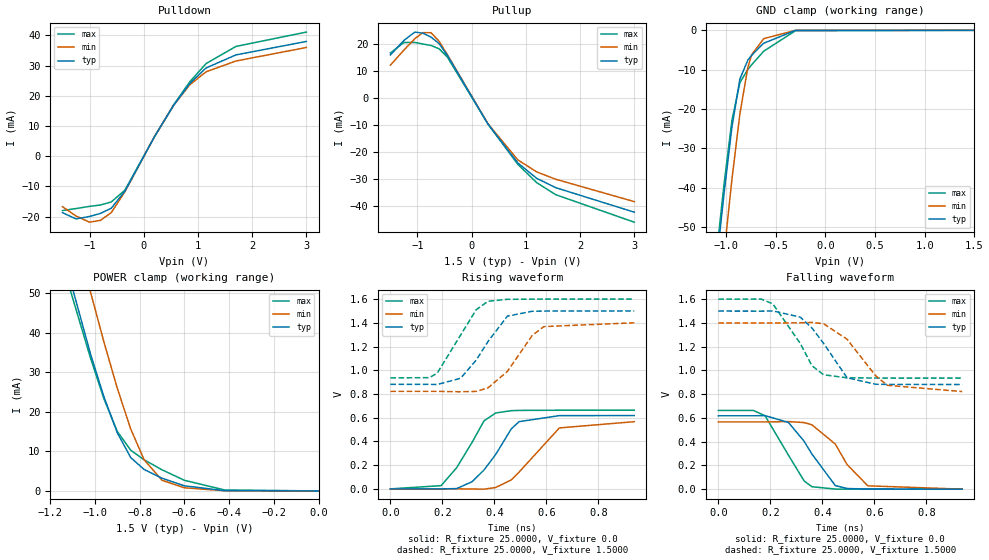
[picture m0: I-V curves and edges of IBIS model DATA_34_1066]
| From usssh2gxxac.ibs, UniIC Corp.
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|   Model DATA_34_1066
[Model]  DATA_34_1066
Model_type I/O
Polarity   Non-Inverting
Enable   Active-High
Vinl =   0.60000000V
Vinh =   0.90000000V
Vmeas =   0.750000000V
Rref =   25.00000000
Vref =   0.75000000V
C_comp   1.6160pF   1.5990pF   1.6430pF
[Temperature Range]   25.0000   95.0000   0.0
[Voltage Range]   1.5000V   1.4000V   1.6000V
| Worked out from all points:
|   slope of the pulldown table from 0 to 0.225 V, typ, clamps not added: 30.8 ohm
|   slope of the pullup table from 0 to 0.225 V, typ, clamps not added: 30.4 ohm
|   GND clamp passes 1 mA (typ) near -0.50 V on its own axis
|   POWER clamp passes 1 mA (typ) near -0.58 V on its own axis
|   rising waveform, R_fixture 25.0000, V_fixture 0.0: 20-80 % time 115ps typ, 130ps min, 108ps max; typ from 0 V to 0.618 V
|   rising waveform, R_fixture 25.0000, V_fixture 1.5000: 20-80 % time 113ps typ, 116ps min, 104ps max; typ from 0.881 V to 1.5 V
|   falling waveform, R_fixture 25.0000, V_fixture 0.0: 20-80 % time 110ps typ, 112ps min, 101ps max; typ from 0.618 V to 0 V
|   falling waveform, R_fixture 25.0000, V_fixture 1.5000: 20-80 % time 112ps typ, 127ps min, 105ps max; typ from 1.5 V to 0.881 V
[Pulldown]
|Voltage   I(typ)   I(min)   I(max)
-1.5V     -18.7mA    -16.7mA    -18mA
-1.25V    -20.76mA   -19.8mA    -17.33mA
-1V       -19.96mA   -21.85mA   -16.61mA
-800mV    -18.94mA   -21.24mA   -16.16mA
-600mV    -17.23mA   -18.69mA   -15.15mA
-350mV    -11.62mA   -11.84mA   -11.29mA
200mV     6.523mA    6.58mA     6.518mA
550mV     16.83mA    16.81mA    16.97mA
850mV     24.09mA    23.66mA    24.66mA
1.15V     29.22mA    27.95mA    30.67mA
1.7V      33.54mA    31.52mA    36.35mA
3V        38mA       36mA       41.1mA
[Pullup]
|Voltage   I(typ)   I(min)   I(max)
-1.5V     15.8mA     12mA       16.5mA
-1.25V    21.14mA    17.6mA     20.39mA
-1.05V    24.23mA    21.76mA    20.4mA
-900mV    23.84mA    24.02mA    19.83mA
-750mV    22.38mA    24mA       19.29mA
-600mV    19.94mA    20.83mA    18.05mA
-450mV    15.66mA    15.92mA    15.03mA
300mV     -9.744mA   -9.622mA   -9.709mA
850mV     -24.07mA   -22.95mA   -24.6mA
1.2V      -29.82mA   -27.44mA   -31.4mA
1.55V     -33.24mA   -30.13mA   -35.83mA
3V        -42.3mA    -38.4mA    -46mA
[GND_clamp]
|Voltage   I(typ)   I(min)   I(max)
-1.5V     -169mA     -189.1mA   -163.8mA
-1.14V    -70.71mA   -88.3mA    -68.32mA
-1.1V     -60.74mA   -77.66mA   -58.33mA
-1.06V    -51.03mA   -67.22mA   -48.61mA
-1.02V    -41.65mA   -57.06mA   -39.27mA
-940mV    -24.55mA   -37.9mA    -22.88mA
-860mV    -12.39mA   -21.26mA   -13.32mA
-780mV    -7.577mA   -9.433mA   -9.942mA
-740mV    -6.329mA   -6.125mA   -8.71mA
-620mV    -3.273mA   -2.113mA   -5.305mA
-300mV    -11.81uA   -4.878uA   -91.71uA
1.5V      4.577nA    23.6nA     33.33nA
[POWER_clamp]
|Voltage   I(typ)   I(min)   I(max)
-1.5V     143.7mA    161.7mA    138.1mA
-1.22V    77.56mA    95.29mA    73.32mA
-1.12V    55.19mA    72.34mA    52.54mA
-1.02V    34.59mA    50.23mA    33.56mA
-960mV    23.77mA    37.63mA    23.28mA
-900mV    14.66mA    25.9mA     15mA
-840mV    8.415mA    15.63mA    10.28mA
-780mV    5.408mA    7.848mA    7.861mA
-700mV    3.206mA    2.693mA    5.332mA
-600mV    1.29mA     794.5uA    2.681mA
-420mV    69.47uA    44.47uA    238.7uA
0V        4.577nA    6.249nA    39.08nA
[Ramp]
| variable   typ   min   max
dV/dt_r  0.3707/0.1151n   0.3398/0.1312n   0.3978/0.1081n
dV/dt_f  0.3712/0.1121n   0.3468/0.1264n   0.3986/0.1049n
R_load = 25.0000
[Rising Waveform]
R_fixture= 25.0000
V_fixture= 0.0
V_fixture_min= 0.0
V_fixture_max= 0.0
|time   V(typ)   V(min)   V(max)
0s        0V         0V         0V
195ps     -137.5uV   111.6uV    27.18mV
255ps     2.544mV    337.2uV    178.8mV
315ps     61.22mV    -1.07mV    395mV
360ps     158.9mV    -2.401mV   573.3mV
405ps     290.2mV    11.68mV    639.6mV
465ps     505.8mV    75.74mV    659.2mV
495ps     566.8mV    141.5mV    661.4mV
650ps     617.4mV    514mV      663mV
938ps     617.9mV    566.4mV    663mV
[Rising Waveform]
R_fixture= 25.0000
V_fixture= 1.5000
V_fixture_min= 1.4000
V_fixture_max= 1.6000
|time   V(typ)   V(min)   V(max)
0s        881.4mV    822mV      935.7mV
150ps     881mV      822.1mV    937.7mV
180ps     879.7mV    822.1mV    975.2mV
270ps     932.4mV    818.6mV    1.296V
330ps     1.085V     821.5mV    1.51V
375ps     1.241V     850.9mV    1.581V
450ps     1.456V     989.9mV    1.598V
545ps     1.497V     1.292V     1.599V
590ps     1.499V     1.368V     1.6V
938ps     1.5V       1.4V       1.6V
[Falling Waveform]
R_fixture= 25.0000
V_fixture= 0.0
V_fixture_min= 0.0
V_fixture_max= 0.0
|time   V(typ)   V(min)   V(max)
0s        617.9mV    566.4mV    663mV
135ps     617.9mV    566.3mV    662.9mV
180ps     619mV      566.3mV    618.1mV
270ps     561.8mV    569.1mV    285.5mV
330ps     403.3mV    560.9mV    69.54mV
360ps     295.8mV    542.3mV    20.56mV
450ps     30.34mV    380.2mV    681.6uV
495ps     5.644mV    208.2mV    119.6uV
575ps     376.6uV    28.24mV    6.884uV
938ps     0V         0V         0V
[Falling Waveform]
R_fixture= 25.0000
V_fixture= 1.5000
V_fixture_min= 1.4000
V_fixture_max= 1.6000
|time   V(typ)   V(min)   V(max)
0s        1.5V       1.4V       1.6V
165ps     1.499V     1.4V       1.601V
210ps     1.501V     1.399V     1.56V
315ps     1.449V     1.401V     1.228V
360ps     1.358V     1.404V     1.04V
405ps     1.228V     1.393V     963.5mV
495ps     938.3mV    1.263V     937.6mV
605ps     883.7mV    955.6mV    935.8mV
650ps     882.1mV    874.7mV    935.7mV
938ps     881.4mV    822.1mV    935.7mV
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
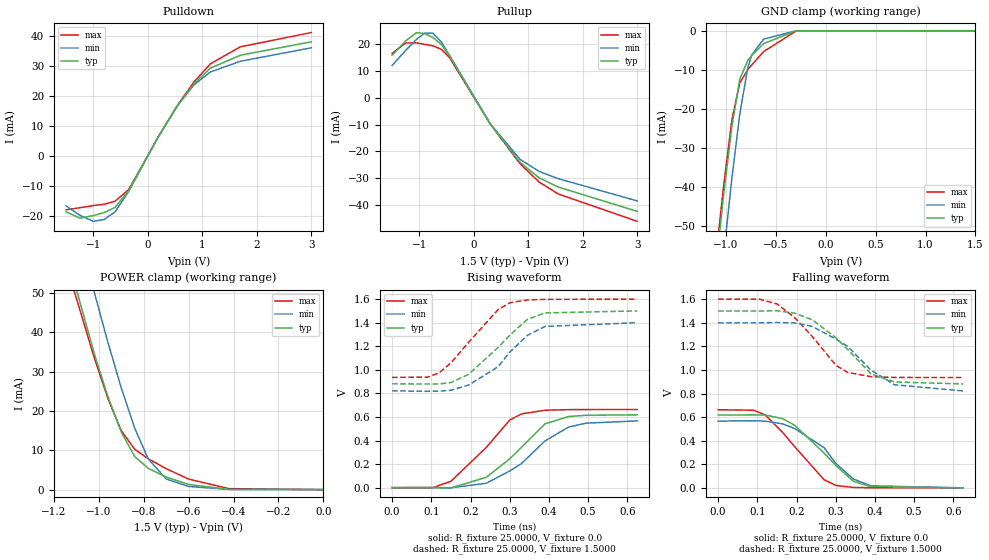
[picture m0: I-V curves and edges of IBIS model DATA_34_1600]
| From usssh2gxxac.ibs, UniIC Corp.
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|   Model DATA_34_1600
[Model]  DATA_34_1600
Model_type I/O
Polarity   Non-Inverting
Enable   Active-High
Vinl =   0.60000000V
Vinh =   0.90000000V
Vmeas =   0.750000000V
Rref =   25.00000000
Vref =   0.75000000V
C_comp   1.6160pF   1.5990pF   1.6430pF
[Temperature Range]   25.0000   95.0000   0.0
[Voltage Range]   1.5000V   1.4000V   1.6000V
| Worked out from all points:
|   slope of the pulldown table from 0 to 0.225 V, typ, clamps not added: 30.8 ohm
|   slope of the pullup table from 0 to 0.225 V, typ, clamps not added: 30.4 ohm
|   GND clamp passes 1 mA (typ) near -0.50 V on its own axis
|   POWER clamp passes 1 mA (typ) near -0.58 V on its own axis
|   rising waveform, R_fixture 25.0000, V_fixture 0.0: 20-80 % time 115ps typ, 125ps min, 108ps max; typ from 0 V to 0.618 V
|   rising waveform, R_fixture 25.0000, V_fixture 1.5000: 20-80 % time 113ps typ, 111ps min, 104ps max; typ from 0.881 V to 1.5 V
|   falling waveform, R_fixture 25.0000, V_fixture 0.0: 20-80 % time 110ps typ, 107ps min, 101ps max; typ from 0.618 V to 0 V
|   falling waveform, R_fixture 25.0000, V_fixture 1.5000: 20-80 % time 112ps typ, 122ps min, 105ps max; typ from 1.5 V to 0.882 V
[Pulldown]
|Voltage   I(typ)   I(min)   I(max)
-1.5V     -18.7mA    -16.7mA    -18mA
-1.25V    -20.76mA   -19.8mA    -17.33mA
-1V       -19.96mA   -21.85mA   -16.61mA
-800mV    -18.94mA   -21.24mA   -16.16mA
-600mV    -17.23mA   -18.69mA   -15.15mA
-350mV    -11.62mA   -11.84mA   -11.29mA
200mV     6.523mA    6.58mA     6.518mA
550mV     16.83mA    16.81mA    16.97mA
850mV     24.09mA    23.66mA    24.66mA
1.15V     29.22mA    27.95mA    30.67mA
1.7V      33.54mA    31.52mA    36.35mA
3V        38mA       36mA       41.1mA
[Pullup]
|Voltage   I(typ)   I(min)   I(max)
-1.5V     15.8mA     12mA       16.5mA
-1.25V    21.14mA    17.6mA     20.39mA
-1.05V    24.23mA    21.76mA    20.4mA
-900mV    23.84mA    24.02mA    19.83mA
-750mV    22.38mA    24mA       19.29mA
-600mV    19.94mA    20.83mA    18.05mA
-450mV    15.66mA    15.92mA    15.03mA
300mV     -9.744mA   -9.622mA   -9.709mA
850mV     -24.07mA   -22.95mA   -24.6mA
1.2V      -29.82mA   -27.44mA   -31.4mA
1.55V     -33.24mA   -30.13mA   -35.83mA
3V        -42.3mA    -38.4mA    -46mA
[GND_clamp]
|Voltage   I(typ)   I(min)   I(max)
-1.5V     -169mA     -189.1mA   -163.8mA
-1.14V    -70.71mA   -88.3mA    -68.32mA
-1.1V     -60.74mA   -77.66mA   -58.33mA
-1.06V    -51.03mA   -67.22mA   -48.61mA
-1.02V    -41.65mA   -57.06mA   -39.27mA
-940mV    -24.55mA   -37.9mA    -22.88mA
-860mV    -12.39mA   -21.26mA   -13.32mA
-780mV    -7.577mA   -9.433mA   -9.942mA
-740mV    -6.329mA   -6.125mA   -8.71mA
-620mV    -3.273mA   -2.113mA   -5.305mA
-300mV    -11.81uA   -4.878uA   -91.71uA
1.5V      4.577nA    23.6nA     33.33nA
[POWER_clamp]
|Voltage   I(typ)   I(min)   I(max)
-1.5V     143.7mA    161.7mA    138.1mA
-1.22V    77.56mA    95.29mA    73.32mA
-1.12V    55.19mA    72.34mA    52.54mA
-1.02V    34.59mA    50.23mA    33.56mA
-960mV    23.77mA    37.63mA    23.28mA
-900mV    14.66mA    25.9mA     15mA
-840mV    8.415mA    15.63mA    10.28mA
-780mV    5.408mA    7.848mA    7.861mA
-700mV    3.206mA    2.693mA    5.332mA
-600mV    1.29mA     794.5uA    2.681mA
-420mV    69.47uA    44.47uA    238.7uA
0V        4.577nA    6.249nA    39.08nA
[Ramp]
| variable   typ   min   max
dV/dt_r  0.3707/0.1151n   0.3398/0.1312n   0.3978/0.1081n
dV/dt_f  0.3712/0.1121n   0.3468/0.1264n   0.3986/0.1049n
R_load = 25.0000
[Rising Waveform]
R_fixture= 25.0000
V_fixture= 0.0
V_fixture_min= 0.0
V_fixture_max= 0.0
|time   V(typ)   V(min)   V(max)
0s        0V         0V         0V
105ps     170.3uV    313.4uV    979.3uV
150ps     -1.852mV   -1.07mV    54.16mV
240ps     87.14mV    37.02mV    340.8mV
300ps     244.2mV    141.5mV    573.3mV
330ps     343.1mV    204.5mV    625.9mV
390ps     541.5mV    396.8mV    657mV
450ps     603.3mV    514mV      662mV
495ps     614.4mV    547.4mV    662.7mV
625ps     617.9mV    566.4mV    663mV
[Rising Waveform]
R_fixture= 25.0000
V_fixture= 1.5000
V_fixture_min= 1.4000
V_fixture_max= 1.6000
|time   V(typ)   V(min)   V(max)
0s        881.4mV    822mV      935.7mV
90.91ps   879.7mV    817.7mV    937.7mV
120ps     880.1mV    818.6mV    975.2mV
150ps     891.6mV    826.5mV    1.059V
195ps     961.6mV    870.7mV    1.233V
270ps     1.189V     1.025V     1.51V
300ps     1.293V     1.15V      1.569V
345ps     1.428V     1.292V     1.593V
390ps     1.483V     1.368V     1.598V
625ps     1.5V       1.4V       1.6V
[Falling Waveform]
R_fixture= 25.0000
V_fixture= 0.0
V_fixture_min= 0.0
V_fixture_max= 0.0
|time   V(typ)   V(min)   V(max)
0s        617.9mV    566.4mV    662.9mV
90.91ps   619mV      569.1mV    658.6mV
120ps     617.7mV    566mV      618.1mV
165ps     586.9mV    542.3mV    468.6mV
195ps     531.4mV    503.8mV    350.2mV
270ps     295.8mV    341.6mV    69.54mV
300ps     190.9mV    208.2mV    20.56mV
345ps     55.27mV    74.32mV    3.695mV
390ps     9.881mV    17.46mV    681.6uV
625ps     0V         0V         0V
[Falling Waveform]
R_fixture= 25.0000
V_fixture= 1.5000
V_fixture_min= 1.4000
V_fixture_max= 1.6000
|time   V(typ)   V(min)   V(max)
0s        1.5V       1.4V       1.6V
105ps     1.5V       1.4V       1.601V
150ps     1.503V     1.403V     1.56V
195ps     1.482V     1.399V     1.445V
240ps     1.426V     1.37V      1.285V
300ps     1.274V     1.263V     1.04V
330ps     1.176V     1.201V     979.3mV
390ps     965.9mV    998.2mV    943.1mV
450ps     898.3mV    874.7mV    936.9mV
625ps     881.5mV    822.1mV    935.7mV
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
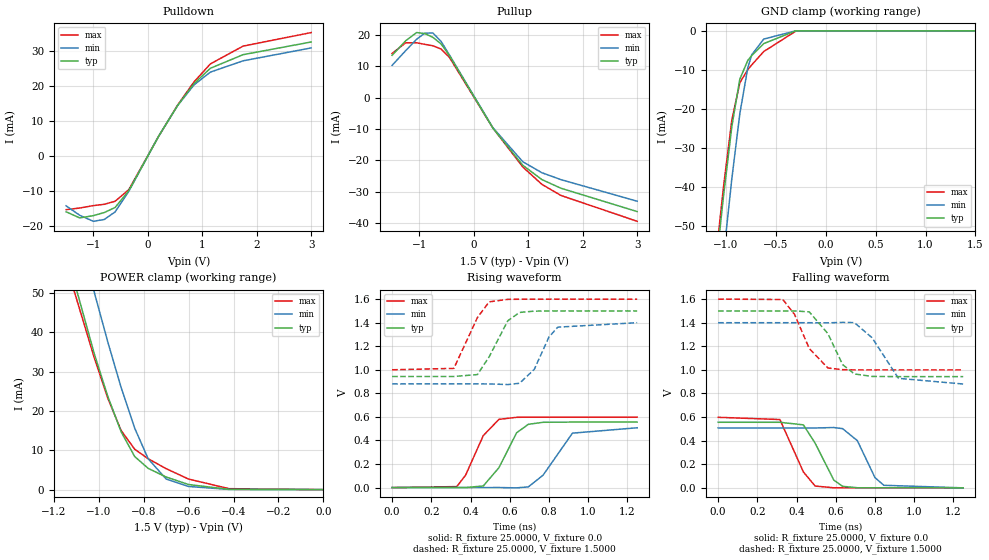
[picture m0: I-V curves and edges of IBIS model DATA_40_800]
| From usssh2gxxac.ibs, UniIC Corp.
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|   Model DATA_40_800
[Model]  DATA_40_800
Model_type I/O
Polarity   Non-Inverting
Enable   Active-High
Vinl =   0.60000000V
Vinh =   0.90000000V
Vmeas =   0.750000000V
Rref =   25.00000000
Vref =   0.75000000V
C_comp   1.6160pF   1.5990pF   1.6430pF
[Temperature Range]   25.0000   95.0000   0.0
[Voltage Range]   1.5000V   1.4000V   1.6000V
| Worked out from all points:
|   slope of the pulldown table from 0 to 0.225 V, typ, clamps not added: 35.8 ohm
|   slope of the pullup table from 0 to 0.225 V, typ, clamps not added: 35.3 ohm
|   GND clamp passes 1 mA (typ) near -0.50 V on its own axis
|   POWER clamp passes 1 mA (typ) near -0.58 V on its own axis
|   rising waveform, R_fixture 25.0000, V_fixture 0.0: 20-80 % time 104ps typ, 113ps min, 96.5ps max; typ from 0 V to 0.556 V
|   rising waveform, R_fixture 25.0000, V_fixture 1.5000: 20-80 % time 102ps typ, 90.8ps min, 93.7ps max; typ from 0.943 V to 1.5 V
|   falling waveform, R_fixture 25.0000, V_fixture 0.0: 20-80 % time 99.1ps typ, 87.6ps min, 91.1ps max; typ from 0.556 V to 0 V
|   falling waveform, R_fixture 25.0000, V_fixture 1.5000: 20-80 % time 102ps typ, 109ps min, 95.2ps max; typ from 1.5 V to 0.943 V
[Pulldown]
|Voltage   I(typ)   I(min)   I(max)
-1.5V     -16mA      -14.3mA    -15.4mA
-1.25V    -17.76mA   -17mA      -14.93mA
-1V       -17.11mA   -18.73mA   -14.24mA
-800mV    -16.23mA   -18.22mA   -13.86mA
-600mV    -14.78mA   -16.05mA   -13mA
-350mV    -9.992mA   -10.19mA   -9.704mA
200mV     5.609mA    5.658mA    5.604mA
550mV     14.47mA    14.45mA    14.59mA
850mV     20.7mA     20.32mA    21.19mA
1.15V     25.08mA    23.98mA    26.33mA
1.75V     28.97mA    27.21mA    31.42mA
3V        32.6mA     30.9mA     35.3mA
[Pullup]
|Voltage   I(typ)   I(min)   I(max)
-1.5V     13.5mA     10.3mA     14.1mA
-1.25V    18.14mA    15mA       17.49mA
-1.05V    20.75mA    18.62mA    17.5mA
-900mV    20.45mA    20.57mA    17mA
-750mV    19.21mA    20.61mA    16.54mA
-600mV    17.13mA    17.9mA     15.49mA
-450mV    13.47mA    13.7mA     12.92mA
350mV     -9.677mA   -9.536mA   -9.657mA
900mV     -21.53mA   -20.42mA   -22.09mA
1.25V     -26.1mA    -23.92mA   -27.61mA
1.6V      -28.86mA   -26.12mA   -31.16mA
3V        -36.3mA    -33mA      -39.4mA
[GND_clamp]
|Voltage   I(typ)   I(min)   I(max)
-1.5V     -169mA     -189.1mA   -163.8mA
-1.14V    -70.71mA   -88.3mA    -68.32mA
-1.1V     -60.74mA   -77.66mA   -58.33mA
-1.06V    -51.03mA   -67.22mA   -48.61mA
-1.02V    -41.65mA   -57.06mA   -39.27mA
-940mV    -24.55mA   -37.9mA    -22.88mA
-860mV    -12.39mA   -21.26mA   -13.32mA
-780mV    -7.577mA   -9.433mA   -9.942mA
-740mV    -6.329mA   -6.125mA   -8.71mA
-620mV    -3.273mA   -2.113mA   -5.305mA
-300mV    -11.81uA   -4.878uA   -91.71uA
1.5V      4.577nA    23.6nA     33.33nA
[POWER_clamp]
|Voltage   I(typ)   I(min)   I(max)
-1.5V     143.7mA    161.7mA    138.1mA
-1.22V    77.56mA    95.29mA    73.32mA
-1.12V    55.19mA    72.34mA    52.54mA
-1.02V    34.59mA    50.23mA    33.56mA
-960mV    23.77mA    37.63mA    23.28mA
-900mV    14.66mA    25.9mA     15mA
-840mV    8.415mA    15.63mA    10.28mA
-780mV    5.408mA    7.848mA    7.861mA
-700mV    3.206mA    2.693mA    5.332mA
-600mV    1.29mA     794.5uA    2.681mA
-420mV    69.47uA    44.47uA    238.7uA
0V        4.577nA    6.249nA    39.08nA
[Ramp]
| variable   typ   min   max
dV/dt_r  0.3336/0.1041n   0.3046/0.1129n   0.3589/96.4996p
dV/dt_f  0.3342/0.1019n   0.3119/0.1089n   0.3600/95.1948p
R_load = 25.0000
[Rising Waveform]
R_fixture= 25.0000
V_fixture= 0.0
V_fixture_min= 0.0
V_fixture_max= 0.0
|time   V(typ)   V(min)   V(max)
0s        0V         0V         0V
330ps     157.1uV    769.7nV    8.258mV
375ps     245.2uV    -5.347uV   105.6mV
465ps     13.51mV    37.31uV    441.1mV
545ps     168.9mV    313.8uV    579.1mV
635ps     465.2mV    -2.504mV   596.6mV
695ps     537.1mV    5.744mV    597.8mV
770ps     554.3mV    105.1mV    598mV
920ps     556mV      462.1mV    598.1mV
1.25ns    556mV      507.7mV    598.1mV
[Rising Waveform]
R_fixture= 25.0000
V_fixture= 1.5000
V_fixture_min= 1.4000
V_fixture_max= 1.6000
|time   V(typ)   V(min)   V(max)
0s        943mV      880.2mV    1V
315ps     943.1mV    880.2mV    1.012V
435ps     959.4mV    880.4mV    1.443V
495ps     1.11V      880mV      1.577V
590ps     1.416V     874.6mV    1.598V
650ps     1.487V     885.9mV    1.599V
725ps     1.498V     1.003V     1.6V
800ps     1.499V     1.278V     1.6V
845ps     1.5V       1.362V     1.6V
1.25ns    1.5V       1.4V       1.6V
[Falling Waveform]
R_fixture= 25.0000
V_fixture= 0.0
V_fixture_min= 0.0
V_fixture_max= 0.0
|time   V(typ)   V(min)   V(max)
0s        556mV      507.7mV    598.1mV
315ps     555.9mV    507.7mV    579.3mV
435ps     534.1mV    507.6mV    134.8mV
495ps     378.3mV    507.7mV    15.11mV
590ps     66mV       511.5mV    582.4uV
635ps     12.97mV    501.9mV    113.9uV
710ps     954.7uV    400.5mV    7.593uV
800ps     27.03uV    87.05mV    0V
845ps     5.312uV    21.79mV    0V
1.25ns    0V         837.3nV    0V
[Falling Waveform]
R_fixture= 25.0000
V_fixture= 1.5000
V_fixture_min= 1.4000
V_fixture_max= 1.6000
|time   V(typ)   V(min)   V(max)
0s        1.5V       1.4V       1.6V
330ps     1.499V     1.4V       1.597V
390ps     1.5V       1.4V       1.47V
465ps     1.492V     1.4V       1.181V
560ps     1.307V     1.399V     1.016V
635ps     1.045V     1.403V     1.002V
695ps     965.7mV    1.401V     1V
785ps     944.6mV    1.273V     1V
920ps     943.1mV    928.4mV    1V
1.25ns    943mV      880.3mV    1V
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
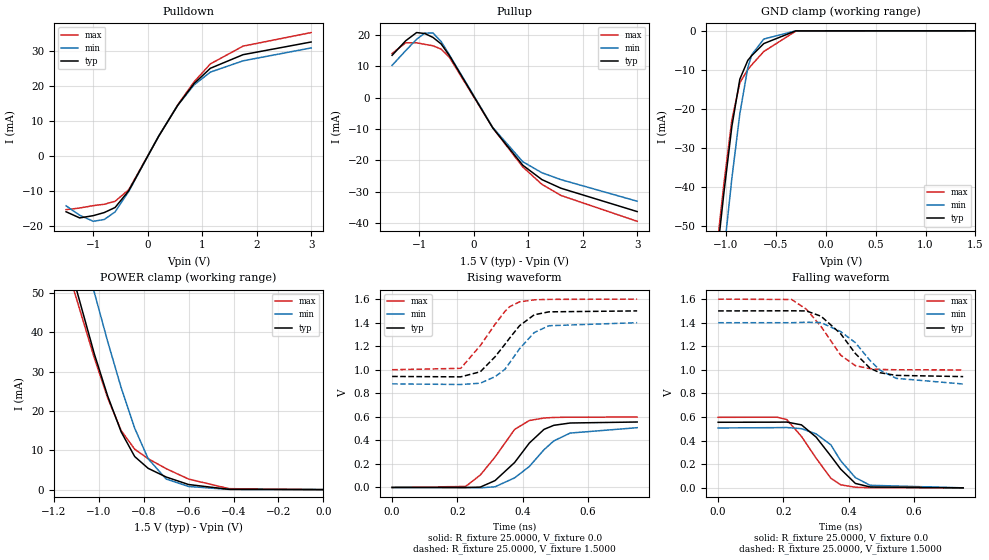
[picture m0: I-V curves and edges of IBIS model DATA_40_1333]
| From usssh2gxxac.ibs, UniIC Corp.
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|   Model DATA_40_1333
[Model]  DATA_40_1333
Model_type I/O
Polarity   Non-Inverting
Enable   Active-High
Vinl =   0.60000000V
Vinh =   0.90000000V
Vmeas =   0.750000000V
Rref =   25.00000000
Vref =   0.75000000V
C_comp   1.6160pF   1.5990pF   1.6430pF
[Temperature Range]   25.0000   95.0000   0.0
[Voltage Range]   1.5000V   1.4000V   1.6000V
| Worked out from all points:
|   slope of the pulldown table from 0 to 0.225 V, typ, clamps not added: 35.8 ohm
|   slope of the pullup table from 0 to 0.225 V, typ, clamps not added: 35.3 ohm
|   GND clamp passes 1 mA (typ) near -0.50 V on its own axis
|   POWER clamp passes 1 mA (typ) near -0.58 V on its own axis
|   rising waveform, R_fixture 25.0000, V_fixture 0.0: 20-80 % time 104ps typ, 115ps min, 96.5ps max; typ from 0 V to 0.556 V
|   rising waveform, R_fixture 25.0000, V_fixture 1.5000: 20-80 % time 96.8ps typ, 90.8ps min, 93.7ps max; typ from 0.943 V to 1.5 V
|   falling waveform, R_fixture 25.0000, V_fixture 0.0: 20-80 % time 94.1ps typ, 87.6ps min, 91.1ps max; typ from 0.556 V to 0 V
|   falling waveform, R_fixture 25.0000, V_fixture 1.5000: 20-80 % time 102ps typ, 111ps min, 95.2ps max; typ from 1.5 V to 0.943 V
[Pulldown]
|Voltage   I(typ)   I(min)   I(max)
-1.5V     -16mA      -14.3mA    -15.4mA
-1.25V    -17.76mA   -17mA      -14.93mA
-1V       -17.11mA   -18.73mA   -14.24mA
-800mV    -16.23mA   -18.22mA   -13.86mA
-600mV    -14.78mA   -16.05mA   -13mA
-350mV    -9.992mA   -10.19mA   -9.704mA
200mV     5.609mA    5.658mA    5.604mA
550mV     14.47mA    14.45mA    14.59mA
850mV     20.7mA     20.32mA    21.19mA
1.15V     25.08mA    23.98mA    26.33mA
1.75V     28.97mA    27.21mA    31.42mA
3V        32.6mA     30.9mA     35.3mA
[Pullup]
|Voltage   I(typ)   I(min)   I(max)
-1.5V     13.5mA     10.3mA     14.1mA
-1.25V    18.14mA    15mA       17.49mA
-1.05V    20.75mA    18.62mA    17.5mA
-900mV    20.45mA    20.57mA    17mA
-750mV    19.21mA    20.61mA    16.54mA
-600mV    17.13mA    17.9mA     15.49mA
-450mV    13.47mA    13.7mA     12.92mA
350mV     -9.677mA   -9.536mA   -9.657mA
900mV     -21.53mA   -20.42mA   -22.09mA
1.25V     -26.1mA    -23.92mA   -27.61mA
1.6V      -28.86mA   -26.12mA   -31.16mA
3V        -36.3mA    -33mA      -39.4mA
[GND_clamp]
|Voltage   I(typ)   I(min)   I(max)
-1.5V     -169mA     -189.1mA   -163.8mA
-1.14V    -70.71mA   -88.3mA    -68.32mA
-1.1V     -60.74mA   -77.66mA   -58.33mA
-1.06V    -51.03mA   -67.22mA   -48.61mA
-1.02V    -41.65mA   -57.06mA   -39.27mA
-940mV    -24.55mA   -37.9mA    -22.88mA
-860mV    -12.39mA   -21.26mA   -13.32mA
-780mV    -7.577mA   -9.433mA   -9.942mA
-740mV    -6.329mA   -6.125mA   -8.71mA
-620mV    -3.273mA   -2.113mA   -5.305mA
-300mV    -11.81uA   -4.878uA   -91.71uA
1.5V      4.577nA    23.6nA     33.33nA
[POWER_clamp]
|Voltage   I(typ)   I(min)   I(max)
-1.5V     143.7mA    161.7mA    138.1mA
-1.22V    77.56mA    95.29mA    73.32mA
-1.12V    55.19mA    72.34mA    52.54mA
-1.02V    34.59mA    50.23mA    33.56mA
-960mV    23.77mA    37.63mA    23.28mA
-900mV    14.66mA    25.9mA     15mA
-840mV    8.415mA    15.63mA    10.28mA
-780mV    5.408mA    7.848mA    7.861mA
-700mV    3.206mA    2.693mA    5.332mA
-600mV    1.29mA     794.5uA    2.681mA
-420mV    69.47uA    44.47uA    238.7uA
0V        4.577nA    6.249nA    39.08nA
[Ramp]
| variable   typ   min   max
dV/dt_r  0.3336/0.1041n   0.3046/0.1129n   0.3589/96.4996p
dV/dt_f  0.3342/0.1019n   0.3119/0.1089n   0.3600/95.1948p
R_load = 25.0000
[Rising Waveform]
R_fixture= 25.0000
V_fixture= 0.0
V_fixture_min= 0.0
V_fixture_max= 0.0
|time   V(typ)   V(min)   V(max)
0s        0V         0V         0V
225ps     -1.177mV   -445.7uV   8.258mV
270ps     3.196mV    -3.475mV   105.6mV
315ps     58.01mV    5.744mV    258.1mV
375ps     212.1mV    81.61mV    493.1mV
420ps     377.3mV    178mV      568.7mV
465ps     493.7mV    321mV      590mV
495ps     527.9mV    395.6mV    594.7mV
545ps     547.6mV    462.1mV    597.1mV
750ps     556mV      507.7mV    598.1mV
[Rising Waveform]
R_fixture= 25.0000
V_fixture= 1.5000
V_fixture_min= 1.4000
V_fixture_max= 1.6000
|time   V(typ)   V(min)   V(max)
0s        943mV      880.2mV    1V
210ps     939.6mV    874.6mV    1.012V
270ps     982.9mV    885.9mV    1.205V
315ps     1.11V      941mV      1.386V
345ps     1.215V     1.003V     1.495V
360ps     1.27V      1.06V      1.536V
390ps     1.374V     1.178V     1.577V
435ps     1.467V     1.316V     1.594V
480ps     1.492V     1.374V     1.598V
750ps     1.5V       1.4V       1.6V
[Falling Waveform]
R_fixture= 25.0000
V_fixture= 0.0
V_fixture_min= 0.0
V_fixture_max= 0.0
|time   V(typ)   V(min)   V(max)
0s        556mV      507.7mV    598.1mV
180ps     557mV      510.5mV    599.1mV
210ps     557.8mV    511.5mV    579.3mV
255ps     534.1mV    501.9mV    436.1mV
300ps     430mV      457.4mV    251mV
345ps     269.6mV    364.7mV    81.51mV
375ps     159.1mV    230.3mV    26.07mV
420ps     37.64mV    87.05mV    5.109mV
465ps     7.592mV    21.79mV    1.015mV
750ps     0V         0V         0V
[Falling Waveform]
R_fixture= 25.0000
V_fixture= 1.5000
V_fixture_min= 1.4000
V_fixture_max= 1.6000
|time   V(typ)   V(min)   V(max)
0s        1.5V       1.4V       1.6V
225ps     1.501V     1.4V       1.597V
270ps     1.5V       1.404V     1.514V
315ps     1.455V     1.401V     1.368V
375ps     1.307V     1.325V     1.125V
420ps     1.139V     1.231V     1.036V
465ps     1.014V     1.079V     1.01V
495ps     976.2mV    998.9mV    1.004V
545ps     953.6mV    928.4mV    1.001V
750ps     943.1mV    880.4mV    1V
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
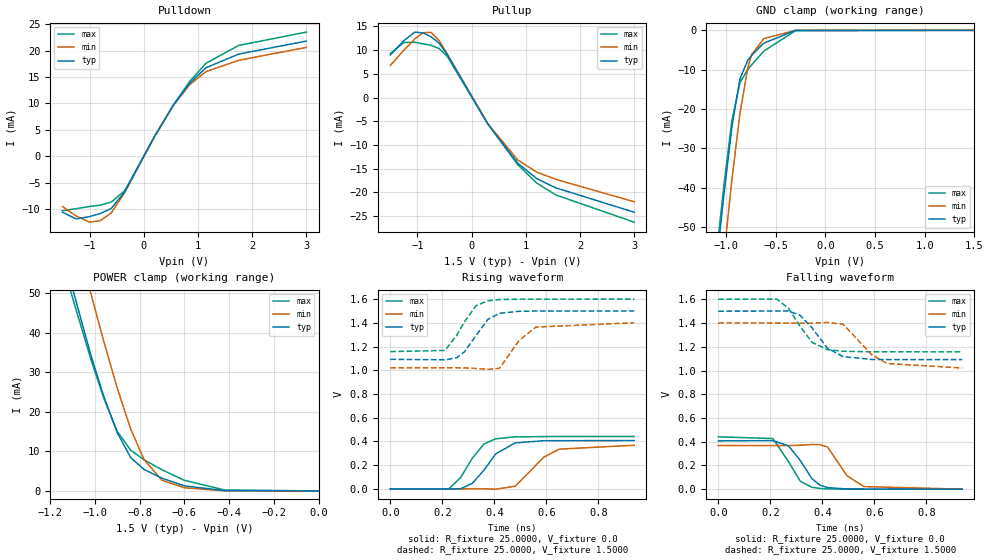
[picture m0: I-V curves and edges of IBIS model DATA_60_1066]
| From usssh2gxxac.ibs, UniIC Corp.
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|   Model DATA_60_1066
[Model]  DATA_60_1066
Model_type I/O
Polarity   Non-Inverting
Enable   Active-High
Vinl =   0.60000000V
Vinh =   0.90000000V
Vmeas =   0.750000000V
Rref =   25.00000000
Vref =   0.75000000V
C_comp   1.6160pF   1.5990pF   1.6430pF
[Temperature Range]   25.0000   95.0000   0.0
[Voltage Range]   1.5000V   1.4000V   1.6000V
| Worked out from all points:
|   slope of the pulldown table from 0 to 0.225 V, typ, clamps not added: 53.4 ohm
|   slope of the pullup table from 0 to 0.225 V, typ, clamps not added: 52.6 ohm
|   GND clamp passes 1 mA (typ) near -0.50 V on its own axis
|   POWER clamp passes 1 mA (typ) near -0.58 V on its own axis
|   rising waveform, R_fixture 25.0000, V_fixture 0.0: 20-80 % time 86.5ps typ, 100ps min, 79ps max; typ from 0 V to 0.407 V
|   rising waveform, R_fixture 25.0000, V_fixture 1.5000: 20-80 % time 78.8ps typ, 81.2ps min, 73.4ps max; typ from 1.09 V to 1.5 V
|   falling waveform, R_fixture 25.0000, V_fixture 0.0: 20-80 % time 75.8ps typ, 75.4ps min, 70.8ps max; typ from 0.407 V to 0 V
|   falling waveform, R_fixture 25.0000, V_fixture 1.5000: 20-80 % time 88.4ps typ, 97.1ps min, 81.8ps max; typ from 1.5 V to 1.09 V
[Pulldown]
|Voltage   I(typ)   I(min)   I(max)
-1.5V     -10.6mA    -9.5mA     -10.3mA
-1.25V    -11.86mA   -11.3mA    -9.93mA
-1V       -11.42mA   -12.48mA   -9.5mA
-800mV    -10.84mA   -12.17mA   -9.25mA
-600mV    -9.882mA   -10.74mA   -8.682mA
-350mV    -6.704mA   -6.838mA   -6.505mA
200mV     3.763mA    3.796mA    3.76mA
550mV     9.696mA    9.684mA    9.781mA
850mV     13.86mA    13.59mA    14.19mA
1.15V     16.76mA    16.02mA    17.61mA
1.75V     19.33mA    18.16mA    20.97mA
3V        21.8mA     20.6mA     23.5mA
[Pullup]
|Voltage   I(typ)   I(min)   I(max)
-1.5V     9mA        6.8mA      9.3mA
-1.25V    12.03mA    10mA       11.63mA
-1.05V    13.82mA    12.36mA    11.68mA
-900mV    13.65mA    13.69mA    11.34mA
-750mV    12.84mA    13.77mA    11.04mA
-600mV    11.47mA    12.01mA    10.35mA
-450mV    9.041mA    9.198mA    8.665mA
300mV     -5.62mA    -5.548mA   -5.6mA
850mV     -13.84mA   -13.18mA   -14.16mA
1.2V      -17.1mA    -15.73mA   -18.03mA
1.55V     -19.04mA   -17.25mA   -20.54mA
3V        -24.2mA    -22mA      -26.3mA
[GND_clamp]
|Voltage   I(typ)   I(min)   I(max)
-1.5V     -169mA     -189.1mA   -163.8mA
-1.14V    -70.71mA   -88.3mA    -68.32mA
-1.1V     -60.74mA   -77.66mA   -58.33mA
-1.06V    -51.03mA   -67.22mA   -48.61mA
-1.02V    -41.65mA   -57.06mA   -39.27mA
-940mV    -24.55mA   -37.9mA    -22.88mA
-860mV    -12.39mA   -21.26mA   -13.32mA
-780mV    -7.577mA   -9.433mA   -9.942mA
-740mV    -6.329mA   -6.125mA   -8.71mA
-620mV    -3.273mA   -2.113mA   -5.305mA
-300mV    -11.81uA   -4.878uA   -91.71uA
1.5V      4.577nA    23.6nA     33.33nA
[POWER_clamp]
|Voltage   I(typ)   I(min)   I(max)
-1.5V     143.7mA    161.7mA    138.1mA
-1.22V    77.56mA    95.29mA    73.32mA
-1.12V    55.19mA    72.34mA    52.54mA
-1.02V    34.59mA    50.23mA    33.56mA
-960mV    23.77mA    37.63mA    23.28mA
-900mV    14.66mA    25.9mA     15mA
-840mV    8.415mA    15.63mA    10.28mA
-780mV    5.408mA    7.848mA    7.861mA
-700mV    3.206mA    2.693mA    5.332mA
-600mV    1.29mA     794.5uA    2.681mA
-420mV    69.47uA    44.47uA    238.7uA
0V        4.577nA    6.249nA    39.08nA
[Ramp]
| variable   typ   min   max
dV/dt_r  0.2442/86.5366p   0.2207/98.3857p   0.2647/78.9981p
dV/dt_f  0.2448/88.3671p   0.2280/97.6364p   0.2658/81.8205p
R_load = 25.0000
[Rising Waveform]
R_fixture= 25.0000
V_fixture= 0.0
V_fixture_min= 0.0
V_fixture_max= 0.0
|time   V(typ)   V(min)   V(max)
0s        0V         0V         0V
225ps     -805.3uV   -18.23uV   1.139mV
270ps     1.751mV    133.5uV    95.42mV
315ps     46.46mV    528.8uV    258.4mV
360ps     157.9mV    548.9uV    378.8mV
405ps     295.1mV    -2.368mV   422mV
480ps     387.4mV    22.31mV    438.4mV
590ps     406mV      267mV      441mV
650ps     406.8mV    335.2mV    441.2mV
938ps     407mV      367.8mV    441.2mV
[Rising Waveform]
R_fixture= 25.0000
V_fixture= 1.5000
V_fixture_min= 1.4000
V_fixture_max= 1.6000
|time   V(typ)   V(min)   V(max)
0s        1.092V     1.02V      1.157V
210ps     1.088V     1.021V     1.167V
255ps     1.105V     1.021V     1.294V
285ps     1.156V     1.02V      1.409V
330ps     1.294V     1.015V     1.545V
375ps     1.429V     1.007V     1.585V
420ps     1.48V      1.017V     1.596V
495ps     1.497V     1.251V     1.599V
560ps     1.499V     1.364V     1.599V
938ps     1.5V       1.4V       1.6V
[Falling Waveform]
R_fixture= 25.0000
V_fixture= 0.0
V_fixture_min= 0.0
V_fixture_max= 0.0
|time   V(typ)   V(min)   V(max)
0s        407mV      367.9mV    441.2mV
210ps     408.9mV    367.7mV    426.7mV
270ps     365mV      367.4mV    232.5mV
315ps     242.9mV    370.3mV    67.61mV
360ps     89.18mV    376.5mV    16.03mV
390ps     34.49mV    375.2mV    6.06mV
420ps     13.4mV     355.8mV    2.344mV
495ps     1.268mV    112.9mV    209.2uV
560ps     131.4uV    21.72mV    32.08uV
938ps     0V         0V         0V
[Falling Waveform]
R_fixture= 25.0000
V_fixture= 1.5000
V_fixture_min= 1.4000
V_fixture_max= 1.6000
|time   V(typ)   V(min)   V(max)
0s        1.5V       1.4V       1.6V
225ps     1.501V     1.4V       1.602V
270ps     1.501V     1.399V     1.524V
315ps     1.464V     1.399V     1.371V
360ps     1.361V     1.399V     1.238V
420ps     1.187V     1.405V     1.176V
480ps     1.117V     1.39V      1.162V
590ps     1.093V     1.133V     1.158V
650ps     1.092V     1.059V     1.158V
938ps     1.092V     1.021V     1.157V
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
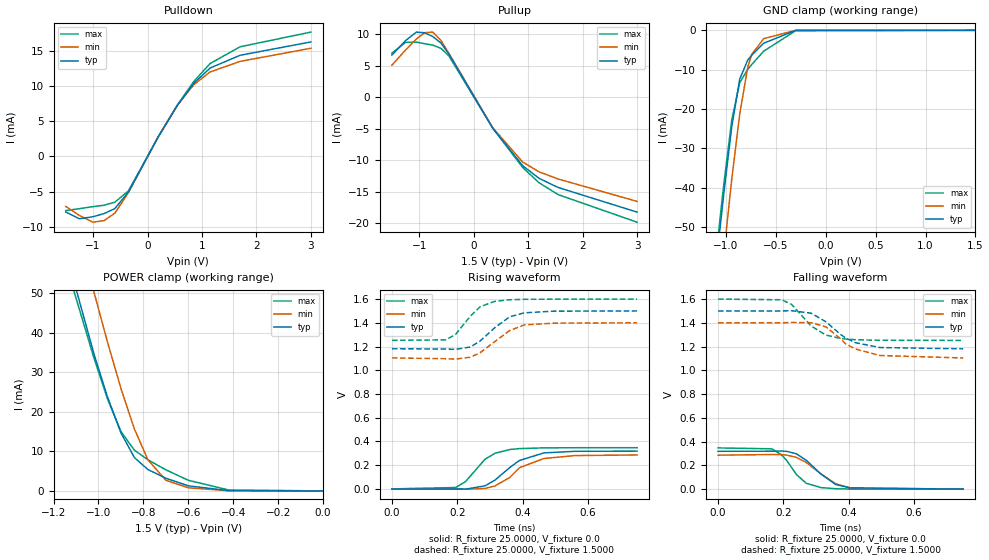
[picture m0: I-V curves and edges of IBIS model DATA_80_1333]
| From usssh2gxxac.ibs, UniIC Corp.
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|   Model DATA_80_1333
[Model]  DATA_80_1333
Model_type I/O
Polarity   Non-Inverting
Enable   Active-High
Vinl =   0.60000000V
Vinh =   0.90000000V
Vmeas =   0.750000000V
Rref =   25.00000000
Vref =   0.75000000V
C_comp   1.6160pF   1.5990pF   1.6430pF
[Temperature Range]   25.0000   95.0000   0.0
[Voltage Range]   1.5000V   1.4000V   1.6000V
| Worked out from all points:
|   slope of the pulldown table from 0 to 0.225 V, typ, clamps not added: 70.9 ohm
|   slope of the pullup table from 0 to 0.225 V, typ, clamps not added: 70 ohm
|   GND clamp passes 1 mA (typ) near -0.50 V on its own axis
|   POWER clamp passes 1 mA (typ) near -0.58 V on its own axis
|   rising waveform, R_fixture 25.0000, V_fixture 0.0: 20-80 % time 91.5ps typ, 90.7ps min, 71.4ps max; typ from 0 V to 0.319 V
|   rising waveform, R_fixture 25.0000, V_fixture 1.5000: 20-80 % time 82.5ps typ, 85.9ps min, 65.7ps max; typ from 1.18 V to 1.5 V
|   falling waveform, R_fixture 25.0000, V_fixture 0.0: 20-80 % time 79.2ps typ, 84.7ps min, 61.1ps max; typ from 0.319 V to 0 V
|   falling waveform, R_fixture 25.0000, V_fixture 1.5000: 20-80 % time 93.8ps typ, 90.3ps min, 77ps max; typ from 1.5 V to 1.18 V
[Pulldown]
|Voltage   I(typ)   I(min)   I(max)
-1.5V     -7.9mA     -7.1mA     -7.7mA
-1.25V    -8.86mA    -8.4mA     -7.43mA
-1V       -8.57mA    -9.35mA    -7.13mA
-800mV    -8.135mA   -9.13mA    -6.94mA
-600mV    -7.422mA   -8.068mA   -6.512mA
-350mV    -5.045mA   -5.146mA   -4.893mA
200mV     2.832mA    2.856mA    2.829mA
550mV     7.292mA    7.282mA    7.356mA
850mV     10.41mA    10.22mA    10.67mA
1.15V     12.59mA    12.03mA    13.23mA
1.7V      14.4mA     13.53mA    15.61mA
3V        16.3mA     15.4mA     17.7mA
[Pullup]
|Voltage   I(typ)   I(min)   I(max)
-1.5V     6.7mA      5.1mA      7mA
-1.25V    9mA        7.5mA      8.72mA
-1.05V    10.35mA    9.26mA     8.76mA
-900mV    10.25mA    10.25mA    8.51mA
-750mV    9.639mA    10.35mA    8.28mA
-600mV    8.621mA    9.028mA    7.779mA
-450mV    6.804mA    6.923mA    6.517mA
350mV     -4.882mA   -4.81mA    -4.873mA
900mV     -10.83mA   -10.26mA   -11.12mA
1.2V      -12.84mA   -11.81mA   -13.54mA
1.55V     -14.29mA   -12.95mA   -15.42mA
3V        -18.2mA    -16.5mA    -19.8mA
[GND_clamp]
|Voltage   I(typ)   I(min)   I(max)
-1.5V     -169mA     -189.1mA   -163.8mA
-1.14V    -70.71mA   -88.3mA    -68.32mA
-1.1V     -60.74mA   -77.66mA   -58.33mA
-1.06V    -51.03mA   -67.22mA   -48.61mA
-1.02V    -41.65mA   -57.06mA   -39.27mA
-940mV    -24.55mA   -37.9mA    -22.88mA
-860mV    -12.39mA   -21.26mA   -13.32mA
-780mV    -7.577mA   -9.433mA   -9.942mA
-740mV    -6.329mA   -6.125mA   -8.71mA
-620mV    -3.273mA   -2.113mA   -5.305mA
-300mV    -11.81uA   -4.878uA   -91.71uA
1.5V      4.577nA    23.6nA     33.33nA
[POWER_clamp]
|Voltage   I(typ)   I(min)   I(max)
-1.5V     143.7mA    161.7mA    138.1mA
-1.22V    77.56mA    95.29mA    73.32mA
-1.12V    55.19mA    72.34mA    52.54mA
-1.02V    34.59mA    50.23mA    33.56mA
-960mV    23.77mA    37.63mA    23.28mA
-900mV    14.66mA    25.9mA     15mA
-840mV    8.415mA    15.63mA    10.28mA
-780mV    5.408mA    7.848mA    7.861mA
-700mV    3.206mA    2.693mA    5.332mA
-600mV    1.29mA     794.5uA    2.681mA
-420mV    69.47uA    44.47uA    238.7uA
0V        4.577nA    6.249nA    39.08nA
[Ramp]
| variable   typ   min   max
dV/dt_r  0.1912/91.4560p   0.1717/0.1057n   0.2083/71.3681p
dV/dt_f  0.1914/93.7667p   0.1776/0.1053n   0.2088/77.0400p
R_load = 25.0000
[Rising Waveform]
R_fixture= 25.0000
V_fixture= 0.0
V_fixture_min= 0.0
V_fixture_max= 0.0
|time   V(typ)   V(min)   V(max)
0s        0V         0V         0V
195ps     -109.1uV   -524.9uV   11.92mV
225ps     -2.146mV   -2.257mV   60.83mV
285ps     25.97mV    3.869mV    250.4mV
315ps     73.35mV    24.51mV    299.8mV
360ps     178.9mV    95.42mV    331.6mV
390ps     239.2mV    178.3mV    339.6mV
465ps     303.6mV    256.1mV    345.9mV
560ps     316.8mV    280.9mV    347mV
750ps     318.6mV    286.1mV    347.2mV
[Rising Waveform]
R_fixture= 25.0000
V_fixture= 1.5000
V_fixture_min= 1.4000
V_fixture_max= 1.6000
|time   V(typ)   V(min)   V(max)
0s        1.181V     1.104V     1.252V
165ps     1.179V     1.097V     1.256V
195ps     1.176V     1.094V     1.303V
240ps     1.196V     1.11V      1.456V
270ps     1.247V     1.148V     1.536V
315ps     1.359V     1.242V     1.581V
360ps     1.45V      1.334V     1.594V
405ps     1.484V     1.382V     1.598V
495ps     1.498V     1.397V     1.599V
750ps     1.5V       1.4V       1.6V
[Falling Waveform]
R_fixture= 25.0000
V_fixture= 0.0
V_fixture_min= 0.0
V_fixture_max= 0.0
|time   V(typ)   V(min)   V(max)
0s        318.6mV    286.1mV    347.2mV
165ps     319.9mV    291.5mV    339.5mV
195ps     320.8mV    290.9mV    287mV
210ps     318.4mV    286.6mV    241.7mV
240ps     297.5mV    267.4mV    122.6mV
270ps     242.8mV    224.3mV    49.29mV
315ps     127.1mV    128.1mV    13.32mV
360ps     39.08mV    45.7mV     3.503mV
405ps     10.66mV    9.695mV    992.8uV
750ps     0V         0V         0V
[Falling Waveform]
R_fixture= 25.0000
V_fixture= 1.5000
V_fixture_min= 1.4000
V_fixture_max= 1.6000
|time   V(typ)   V(min)   V(max)
0s        1.5V       1.4V       1.6V
195ps     1.5V       1.4V       1.594V
225ps     1.502V     1.403V     1.555V
285ps     1.481V     1.401V     1.373V
330ps     1.409V     1.366V     1.297V
375ps     1.302V     1.266V     1.268V
390ps     1.274V     1.224V     1.264V
420ps     1.233V     1.18V      1.258V
495ps     1.192V     1.125V     1.253V
750ps     1.181V     1.104V     1.252V
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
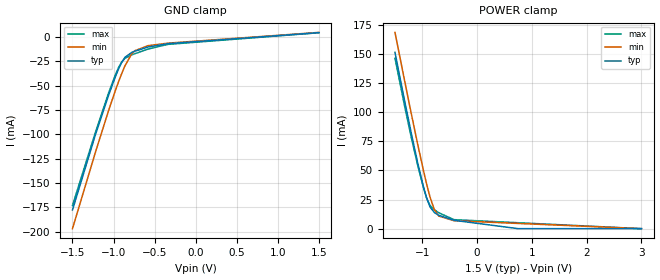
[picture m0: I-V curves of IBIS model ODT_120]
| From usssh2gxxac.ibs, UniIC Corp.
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|   Model ODT_120
[Model]  ODT_120
Model_type Input
Polarity   Non-Inverting
Vinl =   0.60000000V
Vinh =   0.90000000V
C_comp   1.6160pF   1.5990pF   1.6430pF
[Temperature Range]   25.0000   95.0000   0.0
[Voltage Range]   1.5000V   1.4000V   1.6000V
[GND_clamp]
|Voltage   I(typ)   I(min)   I(max)
-1.5V     -177.7mA   -196.9mA   -173.1mA
-1.22V    -100.2mA   -118.2mA   -97.69mA
-1.06V    -59.66mA   -75.39mA   -57.31mA
-980mV    -41.23mA   -55.41mA   -39.16mA
-940mV    -32.98mA   -46.03mA   -31.44mA
-900mV    -25.92mA   -37.25mA   -25.47mA
-860mV    -20.7mA    -29.3mA    -21.78mA
-780mV    -15.76mA   -17.33mA   -18.3mA
-740mV    -14.44mA   -13.93mA   -17.01mA
-580mV    -10.15mA   -8.765mA   -12.28mA
-340mV    -6.759mA   -6.189mA   -7.457mA
1.5V      4.649mA    4.877mA    4.53mA
[POWER_clamp]
|Voltage   I(typ)   I(min)   I(max)
-1.5V     151.4mA    168.5mA    146.3mA
-1.32V    108.9mA    126mA      104.3mA
-1.2V     81.44mA    98.27mA    77.76mA
-1.08V    55.33mA    71.28mA    53.44mA
-980mV    35.92mA    49.88mA    35.14mA
-920mV    26.09mA    37.91mA    25.95mA
-860mV    18.63mA    27.12mA    19.93mA
-780mV    13.81mA    16.11mA    16.26mA
-700mV    11.43mA    10.79mA    13.63mA
-420mV    7.148mA    6.801mA    7.727mA
749.8mV   0A         NA         NA
3V        0A         0A         0A
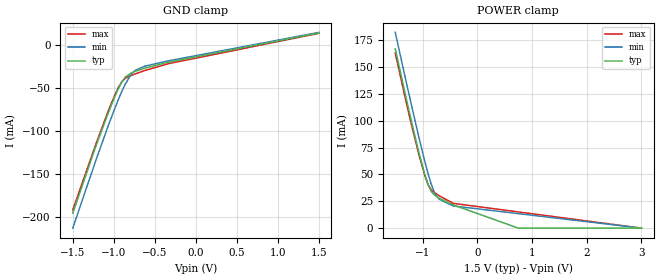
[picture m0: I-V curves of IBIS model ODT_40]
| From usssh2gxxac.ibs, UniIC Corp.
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|   Model ODT_40
[Model]  ODT_40
Model_type Input
Polarity   Non-Inverting
Vinl =   0.60000000V
Vinh =   0.90000000V
C_comp   1.6160pF   1.5990pF   1.6430pF
[Temperature Range]   25.0000   95.0000   0.0
[Voltage Range]   1.5000V   1.4000V   1.6000V
[GND_clamp]
|Voltage   I(typ)   I(min)   I(max)
-1.5V     -195.1mA   -212.5mA   -191.5mA
-1.22V    -117.8mA   -134.3mA   -115.5mA
-1.06V    -76.87mA   -91.72mA   -74.68mA
-980mV    -58.2mA    -71.71mA   -56.35mA
-940mV    -49.83mA   -62.28mA   -48.54mA
-900mV    -42.64mA   -53.42mA   -42.47mA
-860mV    -37.29mA   -45.35mA   -38.69mA
-780mV    -32.08mA   -33.09mA   -34.99mA
-740mV    -30.62mA   -29.51mA   -33.59mA
-620mV    -26.79mA   -24.52mA   -29.57mA
-340mV    -20.15mA   -18.49mA   -21.85mA
1.5V      13.93mA    14.61mA    13.57mA
[POWER_clamp]
|Voltage   I(typ)   I(min)   I(max)
-1.5V     166.7mA    182.1mA    162.8mA
-1.3V     120.7mA    136.1mA    117.1mA
-1.18V    93.97mA    109.1mA    91.05mA
-1.06V    68.61mA    82.85mA    66.93mA
-960mV    49.82mA    62.14mA    48.94mA
-900mV    40.46mA    50.67mA    40.5mA
-840mV    33.91mA    40.5mA     35.62mA
-780mV    30.57mA    32.62mA    33.03mA
-700mV    27.84mA    26.94mA    30.21mA
-440mV    21.61mA    20.62mA    23.05mA
749.7mV   0A         NA         NA
3V        0A         0A         0A
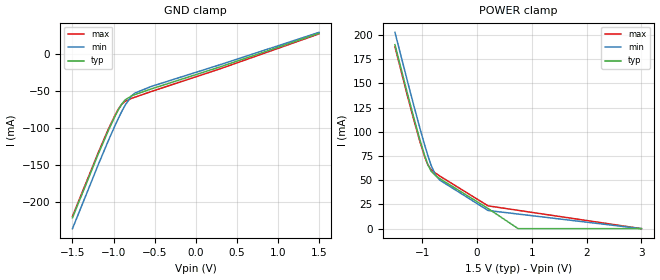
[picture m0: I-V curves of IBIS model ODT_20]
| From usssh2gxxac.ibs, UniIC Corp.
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|   Model ODT_20
[Model]  ODT_20
Model_type Input
Polarity   Non-Inverting
Vinl =   0.60000000V
Vinh =   0.90000000V
C_comp   1.6160pF   1.5990pF   1.6430pF
[Temperature Range]   25.0000   95.0000   0.0
[Voltage Range]   1.5000V   1.4000V   1.6000V
[GND_clamp]
|Voltage   I(typ)   I(min)   I(max)
-1.5V     -221.3mA   -235.9mA   -219.2mA
-1.18V    -133.5mA   -147.8mA   -131.5mA
-1.06V    -102.6mA   -116.2mA   -100.7mA
-980mV    -83.58mA   -96.13mA   -82.07mA
-940mV    -75.02mA   -86.6mA    -74.11mA
-900mV    -67.65mA   -77.61mA   -67.9mA
-860mV    -62.11mA   -69.36mA   -63.98mA
-780mV    -56.5mA    -56.64mA   -59.96mA
-740mV    -54.81mA   -52.79mA   -58.38mA
-540mV    -47.2mA    -43.82mA   -50.68mA
300mV     -17.31mA   -14.36mA   -19.94mA
1.5V      27.81mA    29.14mA    27.1mA
[POWER_clamp]
|Voltage   I(typ)   I(min)   I(max)
-1.5V     189.9mA    202.6mA    187.6mA
-1.28V    141.1mA    153.9mA    138.7mA
-1.16V    115.3mA    127.9mA    113.1mA
-1.04V    90.76mA    102.7mA    88.98mA
-960mV    75.8mA     86.72mA    74.55mA
-900mV    66.18mA    75.46mA    65.95mA
-840mV    59.32mA    65.37mA    60.91mA
-760mV    54.75mA    55.28mA    57.34mA
-680mV    51.59mA    50.03mA    54.25mA
200mV     20.8mA     18.75mA    23.52mA
749.7mV   0A         NA         NA
3V        0A         0A         0A
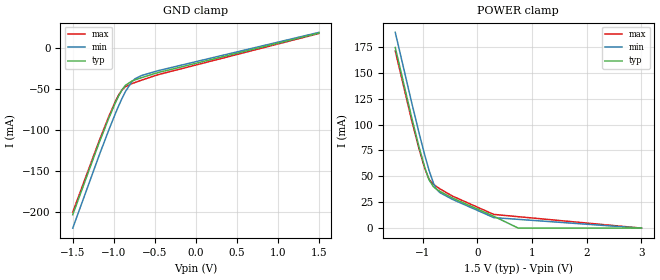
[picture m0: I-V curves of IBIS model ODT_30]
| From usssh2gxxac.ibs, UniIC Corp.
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|   Model ODT_30
[Model]  ODT_30
Model_type Input
Polarity   Non-Inverting
Vinl =   0.60000000V
Vinh =   0.90000000V
C_comp   1.6160pF   1.5990pF   1.6430pF
[Temperature Range]   25.0000   95.0000   0.0
[Voltage Range]   1.5000V   1.4000V   1.6000V
[GND_clamp]
|Voltage   I(typ)   I(min)   I(max)
-1.5V     -203.9mA   -220.3mA   -200.7mA
-1.18V    -116mA     -131.6mA   -113.8mA
-1.06V    -85.46mA   -99.88mA   -83.35mA
-980mV    -66.67mA   -79.85mA   -64.93mA
-940mV    -58.23mA   -70.39mA   -57.07mA
-900mV    -50.99mA   -61.49mA   -50.96mA
-860mV    -45.58mA   -53.36mA   -47.13mA
-780mV    -40.23mA   -40.95mA   -43.33mA
-740mV    -38.69mA   -37.28mA   -41.86mA
-660mV    -35.93mA   -33.33mA   -39.03mA
-460mV    -29.78mA   -27.46mA   -32.37mA
1.5V      18.56mA    19.46mA    18.09mA
[POWER_clamp]
|Voltage   I(typ)   I(min)   I(max)
-1.5V     174.4mA    189mA      171.1mA
-1.2V     106.8mA    121.2mA    104mA
-1.06V    77.31mA    90.84mA    75.58mA
-960mV    58.48mA    70.33mA    57.48mA
-880mV    46.43mA    55.37mA    46.93mA
-800mV    39.85mA    43.19mA    42.2mA
-740mV    37.4mA     37.3mA     39.92mA
-680mV    35.36mA    34.13mA    37.79mA
-460mV    29.22mA    27.91mA    31.08mA
300mV     11.49mA    10.17mA    13.25mA
749.7mV   0A         NA         NA
3V        0A         0A         0A
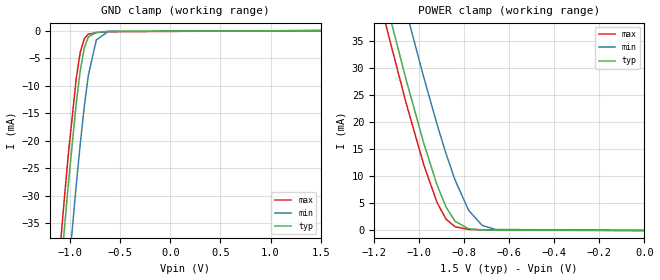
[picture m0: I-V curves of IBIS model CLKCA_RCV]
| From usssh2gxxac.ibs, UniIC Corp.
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|   Model CLKCA_RCV
[Model]  CLKCA_RCV
Model_type Input
Polarity   Non-Inverting
Vinl =   0.60000000V
Vinh =   0.90000000V
C_comp   0.8363pF   0.8227pF   0.8594pF
[Temperature Range]   25.0000   95.0000   0.0
[Voltage Range]   1.5000V   1.4000V   1.6000V
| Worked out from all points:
|   GND clamp passes 1 mA (typ) near -0.81 V on its own axis
|   POWER clamp passes 1 mA (typ) near -0.82 V on its own axis
[GND_clamp]
|Voltage   I(typ)   I(min)   I(max)
-1.5V     -137.6mA   -154.4mA   -131.9mA
-1.14V    -53.62mA   -70.45mA   -47.91mA
-1.1V     -44.81mA   -61.52mA   -39.14mA
-1.06V    -36.22mA   -52.75mA   -30.63mA
-1.02V    -27.95mA   -44.18mA   -22.52mA
-940mV    -13.07mA   -27.92mA   -8.581mA
-900mV    -7.188mA   -20.47mA   -3.873mA
-860mV    -3.14mA    -13.76mA   -1.447mA
-820mV    -1.169mA   -8.138mA   -652.2uA
-740mV    -309.8uA   -1.698mA   -354.4uA
-620mV    -141.6uA   -143.6uA   -209.8uA
1.5V      428.1pA    472.3pA    543.5pA
[POWER_clamp]
|Voltage   I(typ)   I(min)   I(max)
-1.5V     102.9mA    115.8mA    98.51mA
-1.32V    71.56mA    84.52mA    67.09mA
-1.16V    44.42mA    57.36mA    39.98mA
-1.06V    28.22mA    40.96mA    23.91mA
-980mV    16.21mA    28.4mA     12.22mA
-920mV    8.387mA    19.57mA    5.132mA
-880mV    4.308mA    14.14mA    2.067mA
-840mV    1.685mA    9.283mA    678.2uA
-780mV    312.9uA    3.713mA    204.8uA
-720mV    93.05uA    944.1uA    119.2uA
-660mV    42.22uA    183.2uA    74.37uA
0V        428.1pA    310pA      749.3pA
